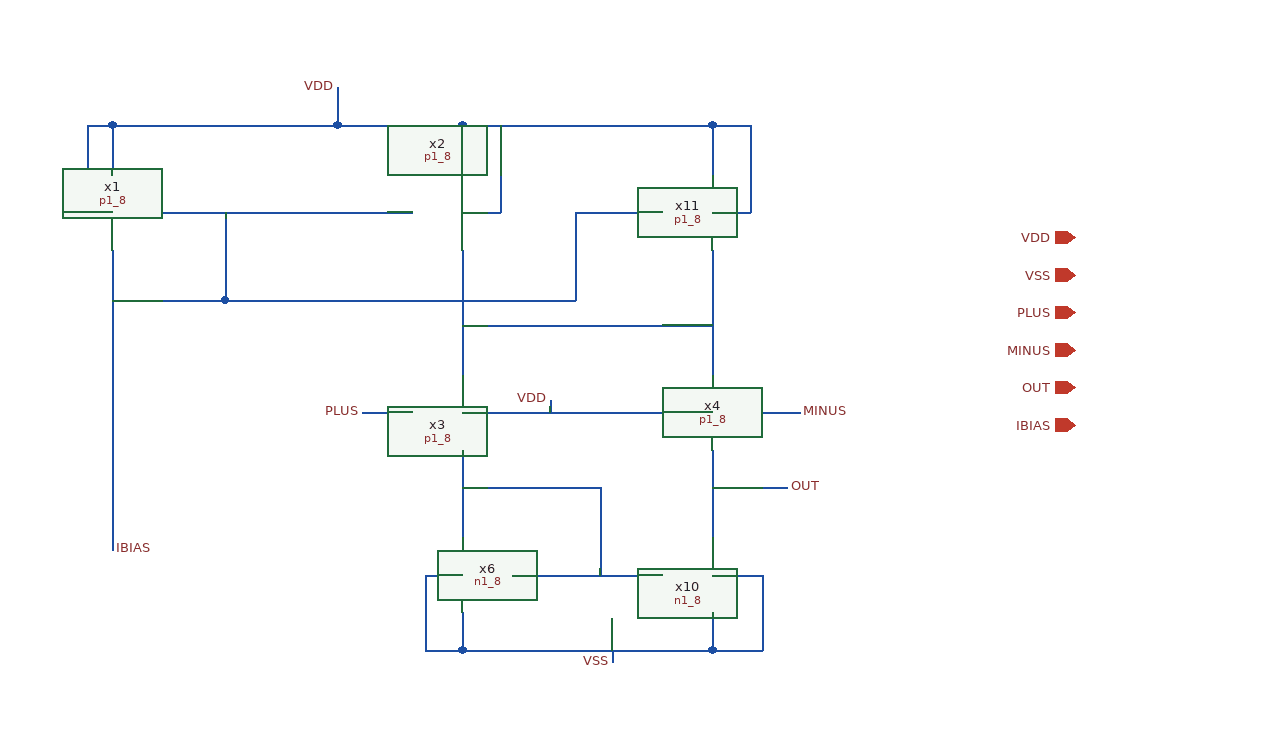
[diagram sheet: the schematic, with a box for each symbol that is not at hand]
v {xschem version=2.9.9 file_version=1.2 }
G {}
K {}
V {}
S {}
E {}
N 110 -490 210 -490 { lab=IBIAS}
N 70 -560 250 -560 { lab=VDD}
N 70 -560 70 -520 { lab=VDD}
N 160 -490 160 -420 { lab=IBIAS}
N 70 -420 160 -420 { lab=IBIAS}
N 50 -490 70 -490 { lab=VDD}
N 50 -560 50 -490 { lab=VDD}
N 50 -560 70 -560 { lab=VDD}
N 70 -460 70 -410 { lab=IBIAS}
N 350 -300 350 -230 { lab=OUT}
N 550 -300 550 -230 { lab=#net1}
N 350 -170 350 -140 { lab=VSS}
N 350 -140 550 -140 { lab=VSS}
N 550 -170 550 -140 { lab=VSS}
N 70 -340 70 -220 { lab=IBIAS}
N 70 -350 70 -340 { lab=IBIAS}
N 270 -330 310 -330 { lab=PLUS}
N 350 -330 550 -330 { lab=VDD}
N 420 -340 420 -330 { lab=VDD}
N 320 -200 350 -200 { lab=VSS}
N 320 -200 320 -140 { lab=VSS}
N 550 -200 590 -200 { lab=VSS}
N 590 -200 590 -140 { lab=VSS}
N 550 -140 590 -140 { lab=VSS}
N 590 -330 620 -330 { lab=MINUS}
N 320 -140 350 -140 { lab=VSS}
N 70 -410 70 -350 { lab=IBIAS}
N 250 -590 250 -560 { lab=VDD}
N 470 -140 470 -130 { lab=VSS}
N 390 -200 420 -200 { lab=#net1}
N 480 -200 510 -200 { lab=#net1}
N 350 -380 350 -360 { lab=#net2}
N 350 -390 350 -380 { lab=#net2}
N 210 -490 310 -490 { lab=IBIAS}
N 550 -460 550 -360 { lab=#net2}
N 350 -460 350 -390 { lab=#net2}
N 350 -560 350 -520 { lab=VDD}
N 250 -560 350 -560 { lab=VDD}
N 550 -560 550 -520 { lab=VDD}
N 350 -560 550 -560 { lab=VDD}
N 160 -420 440 -420 { lab=IBIAS}
N 440 -490 440 -420 { lab=IBIAS}
N 440 -490 510 -490 { lab=IBIAS}
N 350 -490 380 -490 { lab=VDD}
N 380 -560 380 -490 { lab=VDD}
N 550 -490 580 -490 { lab=VDD}
N 550 -560 580 -560 { lab=VDD}
N 580 -560 580 -490 { lab=VDD}
N 350 -400 550 -400 { lab=#net2}
N 420 -200 480 -200 { lab=#net1}
N 550 -270 610 -270 { lab=OUT}
N 350 -270 460 -270 {}
N 460 -270 460 -200 {}
C {devices/lab_pin.sym} 270 -330 0 0 {name=l13 sig_type=std_logic lab=PLUS}
C {devices/lab_pin.sym} 620 -330 2 0 {name=l14 sig_type=std_logic lab=MINUS}
C {devices/lab_pin.sym} 70 -220 2 0 {name=l15 sig_type=std_logic lab=IBIAS}
C {devices/title.sym} 160 -40 0 0 {name=l6 author="LCI Team"}
C {devices/iopin.sym} 840 -470 0 0 {name=p1 lab=VDD}
C {devices/iopin.sym} 840 -440 0 0 {name=p2 lab=VSS}
C {devices/iopin.sym} 840 -410 0 0 {name=p3 lab=PLUS}
C {devices/iopin.sym} 840 -380 0 0 {name=p4 lab=MINUS}
C {devices/iopin.sym} 840 -350 0 0 {name=p5 lab=OUT}
C {devices/iopin.sym} 840 -320 0 0 {name=p6 lab=IBIAS}
C {devices/lab_pin.sym} 250 -590 1 0 {name=l3 sig_type=std_logic lab=VDD}
C {devices/lab_pin.sym} 470 -130 3 0 {name=l1 sig_type=std_logic lab=VSS}
C {devices/lab_pin.sym} 420 -340 1 0 {name=l2 sig_type=std_logic lab=VDD}
C {ARRAY/p1_8.sym} 330 -330 2 1 {name=x3}
C {ARRAY/p1_8.sym} 570 -330 2 0 {name=x4}
C {ARRAY/n1_8.sym} 370 -200 0 1 {name=x6}
C {ARRAY/n1_8.sym} 530 -200 0 0 {name=x10}
C {ARRAY/p1_8.sym} 90 -490 0 1 {name=x1}
C {ARRAY/p1_8.sym} 330 -490 0 0 {name=x2}
C {ARRAY/p1_8.sym} 530 -490 0 0 {name=x11}
C {devices/lab_pin.sym} 610 -270 2 0 {name=l4 sig_type=std_logic lab=OUT}
